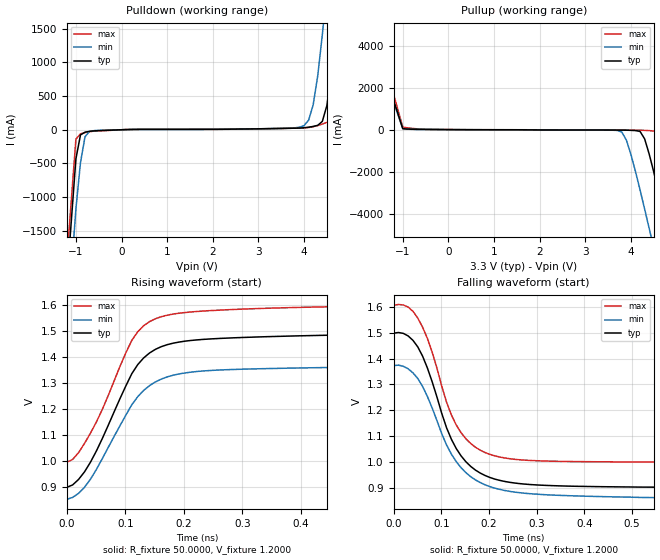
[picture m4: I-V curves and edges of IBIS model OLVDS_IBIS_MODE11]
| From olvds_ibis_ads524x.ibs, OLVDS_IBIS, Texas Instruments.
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|   Model OLVDS_IBIS_MODE11
[Model]   OLVDS_IBIS_MODE11
Model_type   Output
Polarity   Inverting
Vmeas =   1.2000V
Cref =   5.0000pF
Rref = 50.0000
Vref =   1.2000V
C_comp   2.0000pF   1.5000pF   2.5000pF
[Temperature Range]   25.0000   0.1250k   -40.0000
[Voltage Range]   3.3000V   3.0000V   3.6000V
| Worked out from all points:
|   slope of the pulldown table from 0 to 0.495 V, typ, clamps not added: 82.9 ohm
|   slope of the pullup table from 0 to 0.495 V, typ, clamps not added: 107 ohm
|   rising waveform, R_fixture 50.0000, V_fixture 1.2000: 20-80 % time 77.2ps typ, 81.4ps min, 73.6ps max; typ from 0.898 V to 1.49 V
|   falling waveform, R_fixture 50.0000, V_fixture 1.2000: 20-80 % time 75.5ps typ, 84.7ps min, 70ps max; typ from 1.5 V to 0.902 V
[Pulldown]
| voltage   I(typ)   I(min)   I(max)
-3.3V     -22.38A    -23.14A    -21.96A
-2V       -9.6A      -10.42A    -9.138A
-1V       -431.6mA   -1.175A    -140.2mA
-900mV    -77.82mA   -488.9mA   -60.87mA
-800mV    -35.44mA   -102.9mA   -42.72mA
4V        29.73mA    61.13mA    26.94mA
4.2V      49.03mA    370.5mA    44.81mA
4.4V      123.3mA    1.403A     83.63mA
4.5V      358.1mA    2.115A     109.4mA
4.7V      1.54A      3.721A     312mA
4.9V      3.16A      5.456A     1.535A
6.6V      19.22A     21.51A     17.53A
[Pullup]
| voltage   I(typ)   I(min)   I(max)
-3.3V     19.22A     18.61A     20.47A
-2V       6.763A     6.35A      7.855A
-1V       50.09mA    51.48mA    127.1mA
3.8V      -18.92mA   -110.3mA   -15.7mA
4V        -28.39mA   -1.177A    -18.83mA
4.3V      -433.2mA   -3.769A    -29.94mA
4.4V      -1.157A    -4.693A    -42.52mA
4.6V      -2.911A    -6.576A    -139.4mA
4.8V      -4.781A    -8.488A    -1.51A
5.1V      -7.659A    -11.39A    -4.293A
5.2V      -8.628A    -12.36A    -5.251A
6.6V      -22.38A    -26.1A     -18.99A
[Ramp]
| variable   typ   min   max
dV/dt_r   0.3576/76.4434p   0.3099/80.6023p   0.3646/72.8386p
dV/dt_f   0.3578/74.7852p   0.3096/83.9017p   0.3641/69.3506p
R_load = 50.0000
[Rising Waveform]
R_fixture = 50.0000
V_fixture = 1.2000
V_fixture_min = 1.1000
V_fixture_max = 1.3000
| time   V(typ)   V(min)   V(max)
0s        898.1mV    852.1mV    994.6mV
20.2ps    928.8mV    875.2mV    1.032V
40.4ps    994.8mV    929.3mV    1.107V
60.61ps   1.086V     1.008V     1.198V
111.1ps   1.336V     1.216V     1.464V
131.3ps   1.396V     1.271V     1.52V
161.6ps   1.44V      1.315V     1.555V
212.1ps   1.464V     1.342V     1.573V
303ps     1.475V     1.353V     1.585V
1ns       1.494V     1.369V     1.602V
[Falling Waveform]
R_fixture = 50.0000
V_fixture = 1.2000
V_fixture_min = 1.1000
V_fixture_max = 1.3000
| time   V(typ)   V(min)   V(max)
0s        1.498V     1.373V     1.605V
30.3ps    1.487V     1.361V     1.599V
50.51ps   1.445V     1.323V     1.556V
70.71ps   1.364V     1.254V     1.478V
111.1ps   1.132V     1.066V     1.231V
131.3ps   1.053V     1.002V     1.144V
161.6ps   983.8mV    944.2mV    1.072V
202ps     941mV      905.7mV    1.03V
363.6ps   907.9mV    871.1mV    1.003V
1ns       901.7mV    856.8mV    998.6mV
